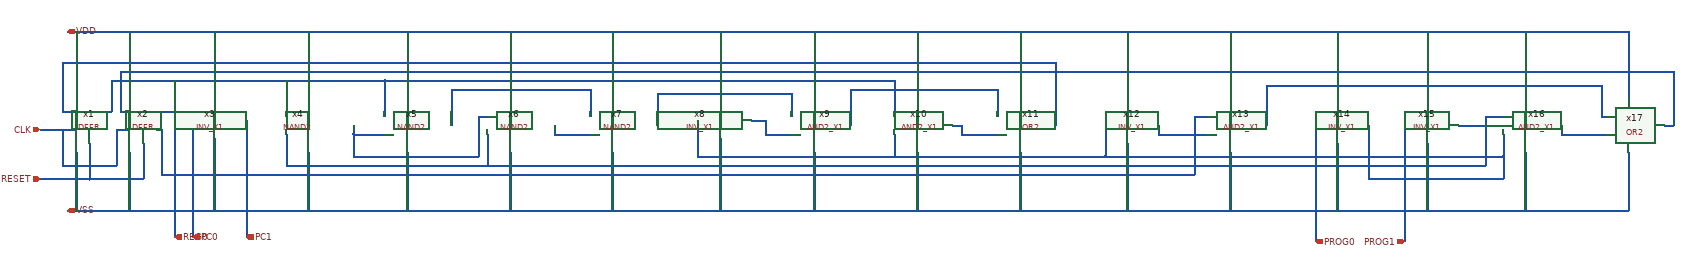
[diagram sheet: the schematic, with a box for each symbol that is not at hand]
v {xschem version=3.4.8RC file_version=1.3}
G {}
K {}
V {}
S {}
F {}
E {}
N 40 -420 3530 -420 {lab=VDD}
N 3530 -420 3530 -270 {lab=VDD}
N 3300 -420 3300 -270 {lab=VDD}
N 3080 -420 3080 -250 {lab=VDD}
N 2880 -420 2880 -250 {lab=VDD}
N 2640 -420 2640 -270 {lab=VDD}
N 2410 -420 2410 -250 {lab=VDD}
N 2170 -420 2170 -270 {lab=VDD}
N 1940 -420 1940 -270 {lab=VDD}
N 1710 -420 1710 -270 {lab=VDD}
N 1500 -420 1500 -260 {lab=VDD}
N 1260 -420 1260 -270 {lab=VDD}
N 1030 -420 1030 -270 {lab=VDD}
N 800 -420 800 -270 {lab=VDD}
N 580 -420 580 -270 {lab=VDD}
N 370 -420 370 -260 {lab=VDD}
N 180 -420 180 -270 {lab=VDD}
N 60 -420 60 -270 {lab=VDD}
N 40 -20 3530 -20 {lab=VSS}
N 3530 -150 3530 -20 {lab=VSS}
N 3300 -150 3300 -20 {lab=VSS}
N 3080 -170 3080 -20 {lab=VSS}
N 2880 -170 2880 -20 {lab=VSS}
N 2640 -150 2640 -20 {lab=VSS}
N 2410 -170 2410 -20 {lab=VSS}
N 2170 -150 2170 -20 {lab=VSS}
N 1940 -150 1940 -20 {lab=VSS}
N 1710 -150 1710 -20 {lab=VSS}
N 1500 -180 1500 -20 {lab=VSS}
N 1260 -150 1260 -20 {lab=VSS}
N 1030 -150 1030 -20 {lab=VSS}
N 800 -150 800 -20 {lab=VSS}
N 580 -150 580 -20 {lab=VSS}
N 370 -180 370 -20 {lab=VSS}
N 180 -150 180 -20 {lab=VSS}
N 60 -150 60 -20 {lab=VSS}
N -20 -200 60 -200 {lab=CLK}
N 30 -200 30 -120 {lab=CLK}
N 30 -120 150 -120 {lab=CLK}
N 150 -200 150 -120 {lab=CLK}
N 150 -200 180 -200 {lab=CLK}
N -20 -90 90 -90 {lab=RESET}
N 90 -170 90 -90 {lab=RESET}
N 90 -90 210 -90 {lab=RESET}
N 210 -170 210 -90 {lab=RESET}
N 750 -310 750 -230 {lab=REG0}
N 140 -310 750 -310 {lab=REG0}
N 140 -310 140 -240 {lab=REG0}
N 120 -240 140 -240 {lab=REG0}
N 280 -310 280 40 {lab=REG0}
N 530 -310 530 -230 {lab=REG0}
N 1890 -300 1890 -230 {lab=REG0}
N 750 -310 1890 -310 {lab=REG0}
N 1890 -310 1890 -300 {lab=REG0}
N 530 -190 530 -120 {lab=#net1}
N 530 -120 980 -120 {lab=#net1}
N 980 -190 980 -120 {lab=#net1}
N 980 -120 3210 -120 {lab=#net1}
N 3210 -230 3210 -120 {lab=#net1}
N 680 -190 750 -190 {lab=#net2}
N 680 -190 680 -140 {lab=#net2}
N 680 -140 960 -140 {lab=#net2}
N 960 -230 960 -140 {lab=#net2}
N 960 -230 980 -230 {lab=#net2}
N 900 -290 900 -210 {lab=#net3}
N 900 -290 1210 -290 {lab=#net3}
N 1210 -290 1210 -230 {lab=#net3}
N 1130 -210 1130 -190 {lab=#net4}
N 1130 -190 1210 -190 {lab=#net4}
N 1360 -280 1360 -210 {lab=#net5}
N 1360 -280 1660 -280 {lab=#net5}
N 1660 -280 1660 -230 {lab=#net5}
N 1570 -220 1600 -220 {lab=#net6}
N 1600 -220 1600 -190 {lab=#net6}
N 1600 -190 1660 -190 {lab=#net6}
N 1890 -190 1890 -140 {lab=#net7}
N 1450 -140 1890 -140 {lab=#net7}
N 1450 -220 1450 -140 {lab=#net7}
N 2360 -210 2360 -140 {lab=#net7}
N 1890 -140 2360 -140 {lab=#net7}
N 3250 -190 3250 -140 {lab=#net7}
N 2360 -140 3250 -140 {lab=#net7}
N 2480 -210 2480 -190 {lab=#net8}
N 2480 -190 2590 -190 {lab=#net8}
N 1790 -290 1790 -210 {lab=#net9}
N 1790 -290 2120 -290 {lab=#net9}
N 2120 -290 2120 -230 {lab=#net9}
N 2020 -210 2040 -210 {lab=#net10}
N 2040 -210 2040 -190 {lab=#net10}
N 2040 -190 2120 -190 {lab=#net10}
N 240 -200 250 -200 {lab=#net11}
N 250 -200 250 -100 {lab=#net11}
N 250 -100 2560 -100 {lab=#net11}
N 2560 -230 2560 -100 {lab=#net11}
N 2560 -230 2590 -230 {lab=#net11}
N 2720 -300 2720 -210 {lab=#net12}
N 2720 -300 3470 -300 {lab=#net12}
N 3470 -300 3470 -230 {lab=#net12}
N 3470 -230 3480 -230 {lab=#net12}
N 3150 -210 3210 -210 {lab=#net1}
N 3030 -210 3030 50 {lab=PROG1}
N 3210 -230 3250 -230 {lab=#net1}
N 3380 -210 3380 -190 {lab=#net13}
N 3380 -190 3480 -190 {lab=#net13}
N 2950 -210 2950 -90 {lab=#net7}
N 2950 -90 3250 -90 {lab=#net7}
N 3250 -140 3250 -90 {lab=#net7}
N 2830 -210 2830 50 {lab=PROG0}
N 2250 -350 2250 -210 {lab=#net14}
N 30 -350 2250 -350 {lab=#net14}
N 30 -350 30 -240 {lab=#net14}
N 30 -240 60 -240 {lab=#net14}
N 160 -240 180 -240 {lab=#net15}
N 160 -330 160 -240 {lab=#net15}
N 160 -330 3630 -330 {lab=#net15}
N 3630 -330 3630 -210 {lab=#net15}
N 3610 -210 3630 -210 {lab=#net15}
N 240 -240 300 -240 {lab=PC0}
N 300 -240 300 -220 {lab=PC0}
N 300 -220 320 -220 {lab=PC0}
N 320 -220 320 40 {lab=PC0}
N 440 -220 440 40 {lab=PC1}
N 680 -210 680 -190 {lab=#net2}
C {DFFR.sym} 90 -210 0 0 {name=x1}
C {DFFR.sym} 210 -210 0 0 {name=x2}
C {INV_X1.sym} 340 -220 0 0 {name=x3}
C {NAND2.sym} 550 -210 0 0 {name=x4}
C {NAND2.sym} 770 -210 0 0 {name=x5}
C {NAND2.sym} 1000 -210 0 0 {name=x6}
C {NAND2.sym} 1230 -210 0 0 {name=x7}
C {INV_X1.sym} 1470 -220 0 0 {name=x8}
C {AND2_X1.sym} 1680 -210 0 0 {name=x9}
C {AND2_X1.sym} 1910 -210 0 0 {name=x10}
C {OR2.sym} 2140 -210 0 0 {name=x11}
C {INV_X1.sym} 2380 -210 0 0 {name=x12}
C {AND2_X1.sym} 2610 -210 0 0 {name=x13}
C {INV_X1.sym} 2850 -210 0 0 {name=x14}
C {INV_X1.sym} 3050 -210 0 0 {name=x15}
C {AND2_X1.sym} 3270 -210 0 0 {name=x16}
C {OR2.sym} 3500 -210 0 0 {name=x17}
C {devices/iopin.sym} 40 -420 0 1 {name=p1 lab=VDD}
C {devices/iopin.sym} 40 -20 0 1 {name=p2 lab=VSS}
C {devices/ipin.sym} -20 -200 0 0 {name=p3 lab=CLK}
C {devices/ipin.sym} -20 -90 0 0 {name=p4 lab=RESET}
C {devices/opin.sym} 280 40 1 0 {name=p5 lab=REG0}
C {devices/ipin.sym} 3030 50 3 0 {name=p6 lab=PROG1}
C {devices/ipin.sym} 2830 50 1 1 {name=p7 lab=PROG0}
C {devices/opin.sym} 320 40 1 0 {name=p8 lab=PC0}
C {devices/opin.sym} 440 40 1 0 {name=p9 lab=PC1}
